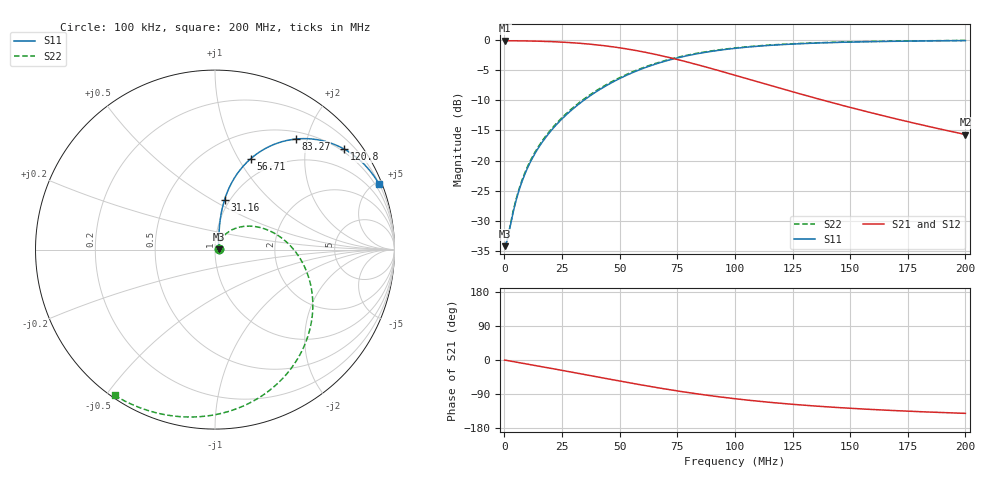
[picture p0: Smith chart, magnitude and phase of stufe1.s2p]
! Created with skrf 2.2.0 (http://scikit-rf.org).
# Hz S RI R 50.0
!freq ReS11 ImS11 ReS21 ImS21 ReS12 ImS12 ReS22 ImS22
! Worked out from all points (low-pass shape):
!   400 points, 100 kHz to 200 MHz, reference 50 ohm
!   highest |S21| = -0.17 dB at 100 kHz (marker M1); lowest = -15.7 dB at 200 MHz (marker M2)
!   |S21| within 3 dB of the highest: start of sweep to 73.98 MHz
!   lowest |S11| = -34.1 dB at 100 kHz (marker M3), VSWR 1.04, Z = 52 + j0.0864 ohm
!   |S11| at or under -10 dB: start of sweep to 34.54 MHz
!   |S22| runs from -34.1 to -0.1 dB; largest |S21 - S12| = 2.2e-16
!   S11 on the Smith chart (normalised r, x): 100 kHz: 1.04, +0.00; 31.16 MHz: 0.95, +0.57; 56.71 MHz: 0.78, +1.13; 83.27 MHz: 0.61, +1.81; 120.8 MHz: 0.43, +2.85; 200 MHz: 0.23, +5.14
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100000  0.0196 0.00083  0.9804 -0.00185  0.9804 -0.00185  0.0196 0.00079
1102005  0.0196 0.00915  0.9801 -0.0203  0.9801 -0.0203  0.02 0.0087
4108020  0.0199 0.0342  0.9768 -0.0758  0.9768 -0.0758  0.0245 0.0321
6112030  0.0203 0.0509  0.9725 -0.1126  0.9725 -0.1126  0.0305 0.0473
8617043  0.0211 0.0721  0.9648 -0.1583  0.9648 -0.1583  0.0411 0.0653
1.162306e7  0.0225 0.0977  0.9519 -0.2125  0.9519 -0.2125  0.0583 0.0849
1.563108e7  0.0252 0.1327  0.9289 -0.2832  0.9289 -0.2832  0.0884 0.1068
2.01401e7  0.03 0.1732  0.8948 -0.36  0.8948 -0.36  0.131 0.1238
3.116216e7  0.053 0.277  0.7765 -0.5278  0.7765 -0.5278  0.2623 0.12
3.366717e7  0.0611 0.3012  0.7432 -0.5606  0.7432 -0.5606  0.2947 0.1087
4.468922e7  0.113 0.4066  0.5752 -0.6731  0.5752 -0.6731  0.4297 0.0107
5.671328e7  0.2001 0.5073  0.3727 -0.7265  0.3727 -0.7265  0.5267 -0.1711
6.673333e7  0.2911 0.5688  0.2133 -0.7164  0.2133 -0.7164  0.5435 -0.3515
7.474937e7  0.3688 0.5999  0.1039 -0.6804  0.1039 -0.6804  0.5141 -0.4929
8.326642e7  0.4503 0.616  0.0103 -0.6249  0.0103 -0.6249  0.4492 -0.6261
1.003005e8  0.5934 0.6079  -0.1084 -0.4952  -0.1084 -0.4952  0.2604 -0.8154
1.103206e8  0.6611 0.5875  -0.1443 -0.4225  -0.1443 -0.4225  0.1384 -0.8795
1.208416e8  0.7193 0.5604  -0.164 -0.3549  -0.164 -0.3549  0.0152 -0.9169
1.333667e8  0.7738 0.5252  -0.1717 -0.2878  -0.1717 -0.2878  -0.1175 -0.9324
1.498997e8  0.8267 0.4795  -0.1675 -0.2193  -0.1675 -0.2193  -0.2655 -0.9221
1.669338e8  0.8653 0.4367  -0.1554 -0.1677  -0.1554 -0.1677  -0.3879 -0.8917
2e8  0.9119 0.3682  -0.1275 -0.1039  -0.1275 -0.1039  -0.5579 -0.8128
